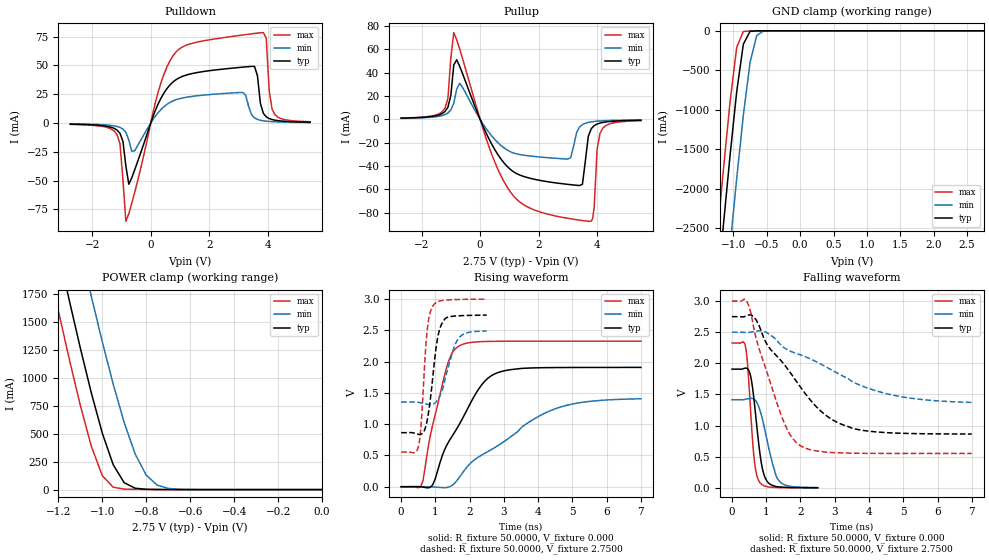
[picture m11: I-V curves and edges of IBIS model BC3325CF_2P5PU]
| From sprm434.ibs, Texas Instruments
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|   Model BC3325CF_2P5PU
[Model]   BC3325CF_2P5PU
Model_type   I/O
Polarity   Non-Inverting
Enable   Active-Low
Vinl =   0.8250V
Vinh =   1.9250V
Vmeas =   1.3750V
Cref =  15.0000pF
Rref = 100.0000M
Vref =  0.000V
C_comp   3.2189pF   3.2468pF   3.2081pF
[Temperature Range]   25.0000   0.1250k   -40.0000
[Voltage Range]   2.7500V   2.5000V   3.0000V
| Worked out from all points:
|   slope of the pulldown table from 0 to 0.412 V, typ, clamps not added: 16.9 ohm
|   slope of the pullup table from 0 to 0.412 V, typ, clamps not added: 18.8 ohm
|   GND clamp passes 1 mA (typ) near -0.66 V on its own axis
|   POWER clamp passes 1 mA (typ) near -0.74 V on its own axis
|   rising waveform, R_fixture 50.0000, V_fixture 0.000: 20-80 % time 1.09ns typ, 2.14ns min, 563ps max; typ from 0 V to 1.91 V
|   rising waveform, R_fixture 50.0000, V_fixture 2.7500: 20-80 % time 247ps typ, 347ps min, 173ps max; typ from 0.864 V to 2.74 V
|   falling waveform, R_fixture 50.0000, V_fixture 0.000: 20-80 % time 243ps typ, 367ps min, 177ps max; typ from 1.91 V to 0.002 V
|   falling waveform, R_fixture 50.0000, V_fixture 2.7500: 20-80 % time 1.62ns typ, 2.52ns min, 867ps max; typ from 2.75 V to 0.865 V
[Pulldown]
| voltage   I(typ)   I(min)   I(max)
-2.75V    -942uA     -650uA     -1.139mA
-1.15V    -6.094mA   -2.984mA   -10.11mA
-850mV    -37.32mA   -8.055mA   -85.3mA
-550mV    -40.73mA   -24mA      -60.28mA
350mV     21.58mA    11.77mA    34.96mA
1.05V     40.19mA    21.58mA    65.58mA
3.15V     48.55mA    26.51mA    76.47mA
3.55V     49.14mA    4.497mA    77.79mA
3.85V     8.53mA     1.96mA     78.58mA
3.95V     5.417mA    1.638mA    73.77mA
4.15V     3.05mA     1.228mA    12mA
5.45V     763uA      461uA      1.156mA
[Pullup]
| voltage   I(typ)   I(min)   I(max)
-2.7V     968uA      800uA      1.062mA
-1.2V     6.635mA    4.013mA    9.529mA
-900mV    46.54mA    13.78mA    74.18mA
-700mV    45.39mA    30.78mA    60.33mA
1V        -42.09mA   -27.31mA   -60.87mA
3V        -55.65mA   -33.97mA   -84.69mA
3.4V      -56.64mA   -6.606mA   -86.26mA
3.7V      -14.63mA   -2.671mA   -87.25mA
3.9V      -5.453mA   -1.879mA   -75.6mA
4V        -4.071mA   -1.633mA   -26.15mA
4.1V      -3.234mA   -1.443mA   -12mA
5.5V      -811uA     -542uA     -1.185mA
[GND_clamp]
| voltage   I(typ)   I(min)   I(max)
-2.75V    -17.96A    -19.08A    -17.31A
-1.25V    -3.392A    -4.569A    -2.686A
-1.15V    -2.474A    -3.647A    -1.77A
-1.05V    -1.588A    -2.744A    -906.6mA
-950mV    -773.4mA   -1.875A    -209.8mA
-850mV    -168.5mA   -1.068A    -8.87mA
-750mV    -7.245mA   -403.2mA   -844.6uA
-650mV    -236.1uA   -59.87mA   -60.92uA
-550mV    -10.55uA   -3.927mA   -2.654uA
2.75V     215.9pA    235.1nA    195pA
[POWER_clamp]
| voltage   I(typ)   I(min)   I(max)
-2.75V    17.1A      17.93A     16.63A
-1.25V    2.586A     3.492A     2.054A
-1.2V     2.135A     3.04A      1.604A
-1.15V    1.695A     2.594A     1.168A
-1.05V    867.5mA    1.733A     390.3mA
-1V       506.5mA    1.325A     124.9mA
-950mV    221.4mA    942.3mA    20.88mA
-900mV    61.07mA    598.5mA    4.539mA
-850mV    12.29mA    317.3mA    2.127mA
-800mV    3.014mA    129mA      1.191mA
-750mV    1.14mA     39.91mA    598.9uA
0V        215.9pA    1.374nA    232.1pA
[Ramp]
| variable   typ   min   max
dV/dt_r   1.0388/0.9478n   0.3351/0.5328n   1.3934/0.5547n
dV/dt_f   0.8897/1.1638n   0.2950/0.8922n   1.4469/0.8387n
R_load = 50.0000
[Rising Waveform]
R_fixture = 50.0000
V_fixture = 0.000
V_fixture_min = 0.000
V_fixture_max = 0.000
| time   V(typ)   V(min)   V(max)
0s        1.107nV    5.38nV     804.8pV
565.7ps   -1.538mV   1.087mV    -5.912mV
636.4ps   -6.011mV   1.098mV    93.75mV
919.2ps   29.12mV    -2.162mV   984.8mV
1.343ns   675.8mV    -11.43mV   1.937V
1.697ns   995.9mV    149.6mV    2.253V
2.333ns   1.616V     500.3mV    2.319V
2.899ns   1.838V     684mV      2.325V
4.596ns   1.905V     1.264V     2.327V
7ns       1.907V     1.406V     2.327V
[Rising Waveform]
R_fixture = 50.0000
V_fixture = 2.7500
V_fixture_min = 2.5000
V_fixture_max = 3.0000
| time   V(typ)   V(min)   V(max)
0s        863.9mV    1.353V     553.4mV
505.1ps   837.4mV    1.349V     643.4mV
580.8ps   838.5mV    1.341V     979.1mV
757.6ps   1.053V     1.318V     2.489V
909.1ps   1.673V     1.317V     2.873V
1.061ns   2.366V     1.383V     2.957V
1.263ns   2.673V     1.668V     2.982V
1.515ns   2.726V     2.18V      2.99V
1.692ns   2.733V     2.381V     2.993V
2.5ns     2.744V     2.489V     2.999V
[Falling Waveform]
R_fixture = 50.0000
V_fixture = 0.000
V_fixture_min = 0.000
V_fixture_max = 0.000
| time   V(typ)   V(min)   V(max)
0s        1.907V     1.416V     2.327V
404ps     1.925V     1.424V     2.242V
454.5ps   1.914V     1.431V     1.984V
530.3ps   1.828V     1.438V     1.358V
631.3ps   1.472V     1.429V     554mV
782.8ps   698.6mV    1.3V       113.1mV
883.8ps   321.7mV    1.112V     48.66mV
984.8ps   143.1mV    868.5mV    25mV
1.364ns   16.08mV    121.2mV    5.153mV
2.5ns     2.324mV    5.294mV    619.2uV
[Falling Waveform]
R_fixture = 50.0000
V_fixture = 2.7500
V_fixture_min = 2.5000
V_fixture_max = 3.0000
| time   V(typ)   V(min)   V(max)
0s        2.75V      2.5V       3V
424.2ps   2.762V     2.498V     3.006V
636.4ps   2.746V     2.51V      2.569V
1.061ns   2.271V     2.479V     1.792V
1.414ns   2.055V     2.303V     1.202V
1.98ns    1.634V     2.14V      684.2mV
2.687ns   1.189V     1.961V     578.1mV
3.535ns   953.6mV    1.697V     557mV
4.949ns   877.4mV    1.464V     553.7mV
7ns       864.9mV    1.372V     553.5mV
